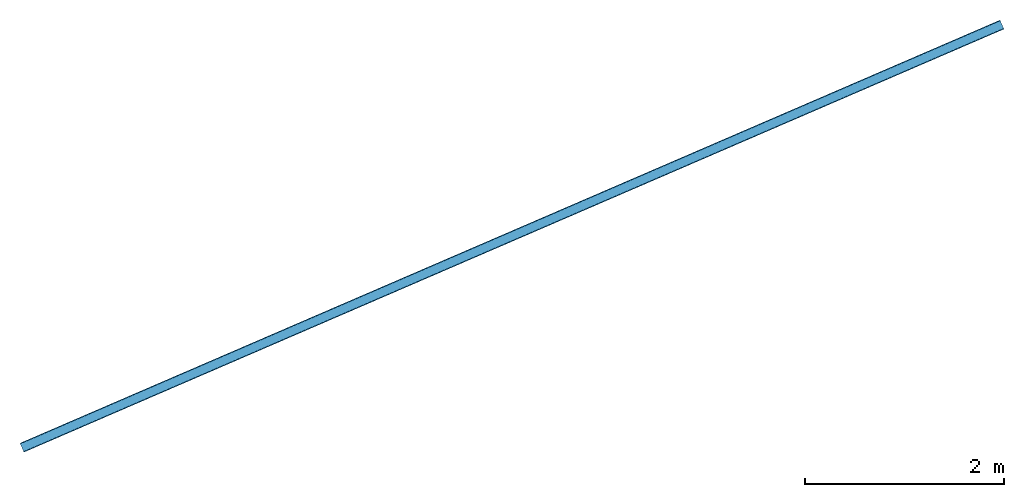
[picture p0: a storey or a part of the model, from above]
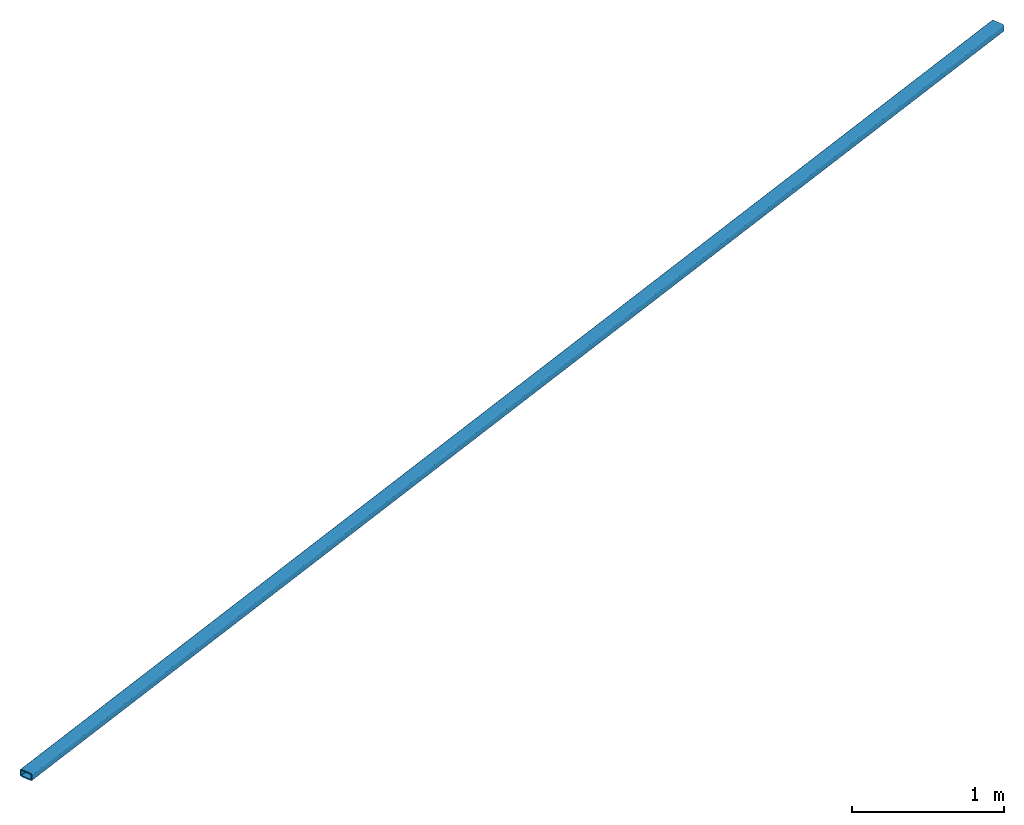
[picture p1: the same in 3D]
Properties of the parts of a building model (IFC4)

# File
Description: ViewDefinition [ReferenceView_V1.2], RevitIdentifiers [ContentGUID: 571f5c7f-810b-4b2c-baeb-ece62dd2b8b9, VersionGUID: cf4ed1ed-50e6-4d82-a1ad-c18ab90050e2, NumberOfSaves: 3], CoordinateReference [CoordinateBase: Shared Coordinates, ProjectSite: Interno]
File name: C:\Users\Joaquin\Dropbox\BuildingProjects\2024 - Construcción Cesfam Coyhaique Con Sar Adosado\2_Modelos\all_models_2025-1-24_23.4.48\CCY_COOR-CCY_EST_CubAmb_Enriched.ifc
Time: 2025-10-28T00:34:42-03:00
Written by: IfcOpenShell 0.8.3-post1
Made in: Bonsai 0.8.3-post1

# IfcProject, 2016_3
LongName: CESFAM Coyhaique; Phase: 3

# IfcSite, Default
RefLatitude: 42, 21, 31, 181945; RefLongitude: -71, -3, -24, -263305; RefElevation: 0 m
Pset_SiteCommon - Reference: Project Information
Other - Category: Project Information; Client Name: Servicio de Salud Aysén; Project Address: Calle 2, s/n. Lote 1C.; Project Issue Date: Marzo 2017; Project Name: CESFAM Coyhaique; Project Number: 2016_3; Project Status: 3
Identity Data - Author: Astudillo y Aparicio Asociados Ltda.; Organization Description: Arquitectura e ingeniería integrada; Organization Name: Astudillo y Aparicio Asociados Ltda.

# IfcBuilding
Pset_BuildingCommon - Reference: Project Information; NumberOfStoreys: 3
Pset_BuildingElementProxyCommon - Reference: Project Information; IsExternal: no
Pset_BuildingSystemCommon - Reference: Project Information
Other - Category: Project Information; Client Name: Servicio de Salud Aysén; Project Address: Calle 2, s/n. Lote 1C.; Project Issue Date: Marzo 2017; Project Name: CESFAM Coyhaique; Project Number: 2016_3; Project Status: 3
Identity Data - Author: Astudillo y Aparicio Asociados Ltda.; Organization Description: Arquitectura e ingeniería integrada; Organization Name: Astudillo y Aparicio Asociados Ltda.

# IfcBuildingStorey: Level:8mm Head (3)
Other - Category: Levels; Family: Level; Family and Type: Level: 8mm Head; Type: 8mm Head; Type Id: 27
Dimensions - Computation Height: 0 m
Identity Data - Structural: no; Building Story: yes
Other(Type) - Category: Levels; Family Name: Level
Constraints(Type) - Elevation Base: Project Base Point
Graphics(Type) - Color: 0; Line Pattern: Center; Line Weight: 1; Symbol: M_Level Head - Circle; Symbol at End 1 Default: no; Symbol at End 2 Default: yes
Identity Data(Type) - Type Name: 8mm Head
Name | LongName = Name | Elevation (m) = Constraints, Elevation (m)
Level 1 | Level 1 | 0
Level 2 | Level 2 | 4.25
Level 3 | Level 3 | 6.875

# IfcBeam: M_HSS Cuadrado:10x6 (3)
Type - PredefinedType: BEAM; Material: Acero, 45-345
Type - Other - Category: Structural Framing; Family Name: M_HSS Cuadrado
Type - Dimensions - Wall Design Thickness: 0.00886 m
Type - Identity Data - Code Name: AISC 14.1; OmniClass Number: 23.25.30.11.14.14; OmniClass Title: Beams; Section Name Key: HSS 6X6X3/8; Type Name: 10x6
Type - Structural - Section Shape: 14
Type - Structural Analysis - Elastic Modulus strong axis: 0.000216 m3; Elastic Modulus weak axis: 0.000216 m3; Moment of Inertia strong axis: 0.0000164 m4; Moment of Inertia weak axis: 0.0000164 m4; Nominal Weight: 400.11 kg/s2; Plastic Modulus strong axis: 0.000259 m3; Plastic Modulus weak axis: 0.000259 m3; Section Area: 0.00489 m2; Torsional Modulus: 5.93212 m3; Torsional Moment of Inertia: 0.0000269 m4
Type - Structural Section Geometry - Centroid Horizontal: 0.05 m; Centroid Vertical: 0.03 m; Height: 0.06 m; Inner Fillet: 0.00347 m; Outer Fillet: 0.013 m; Wall Nominal Thickness: 0.00953 m; Width: 0.1 m
Type - Pset_BeamCommon - LoadBearing: yes
Classification: B103 (FEMAP58); Material: Acero, 45-345; Acero, 45-345
Pset_BeamCommon - Slope: 0 deg; Roll: 0 deg; IsExternal: no; Reference: M_HSS Cuadrado:10x6; Span: 10.715 m
Pset_EnvironmentalImpactIndicators - Reference: M_HSS Cuadrado:10x6; sets with these values: 2
Qto_BeamBaseQuantities - Length: 10.715 m; CrossSectionArea: 0.00585482 m2; OuterSurfaceArea: 3.18966 m2; GrossSurfaceArea: 3.20137 m2; NetSurfaceArea: 5.74281 m2; GrossVolume: 0.0627344 m3; NetVolume: 0.0273398 m3
Other - Family: M_HSS Cuadrado; Family and Type: M_HSS Cuadrado: 10x6; Type: 10x6; Type Id: 204418
Constraints - Cross-Section Rotation: 0 deg
Dimensions - Length: 10.715 m; Volume: 0.0273398 m3
Materials and Finishes - Structural Material: Acero, 45-345
Phasing - Phase Created: New Construction
Structural - Stick Symbol Location: Center of Geometry; Structural Usage: Other; Cut Length: 10.715 m; Weight: 411.261 kg
Geometric Position - End Extension: 0 m; Join Status: Both joins enabled; Start Extension: 0 m; y Justification: Origin; y Offset Value: 0 m; yz Justification: Uniform; z Justification: Center; z Offset Value: 0 m
AboveGround - AboveGround: yes
Name (M_HSS Cuadrado:10x6:...) | In | Reference Level | Reference Level Elevation (m) | End Level Offset (m) = Start Level Offset (m) | Elevation at Bottom (m) | Elevation at Top (m)
205633 | Level 1 | Level 1 | 0 | 0.2 | 0.17 | 0.23
206063 | Level 2 | Level 2 | 4.25 | 0 | 4.22 | 4.28
206123 | Level 3 | Level 3 | 6.875 | -0.03 | 6.815 | 6.875

# IfcBeam: M_HSS-Tubo estructural redondo:HSS190.5X12.7 (9)
In: Level 1
Type - PredefinedType: BEAM; Material: Acero, 45-345
Type - Other - Category: Structural Framing; Family Name: M_HSS-Tubo estructural redondo
Type - Dimensions - OD: 0.15 m; t: 0.0118 m
Type - Identity Data - OmniClass Number: 23.25.30.11.14.14; OmniClass Title: Beams; Type Name: HSS190.5X12.7
Type - Structural - A: 0.00663 m2; Section Shape: 0; W: 0.546
Type - Pset_BeamCommon - LoadBearing: yes
Classification: B103 (FEMAP58); Material: Acero, 45-345; Acero, 45-345
Pset_BeamCommon - Reference: M_HSS-Tubo estructural redondo:HSS190.5X12.7; Slope: 0 deg; Roll: 0 deg; IsExternal: no
Pset_EnvironmentalImpactIndicators - Reference: M_HSS-Tubo estructural redondo:HSS190.5X12.7; sets with these values: 2
Qto_BeamBaseQuantities - CrossSectionArea: 0.0176691 m2
Other - Family: M_HSS-Tubo estructural redondo; Family and Type: M_HSS-Tubo estructural redondo: HSS190.5X12.7; Type: HSS190.5X12.7; Type Id: 199820
Constraints - Cross-Section Rotation: 0 deg; End Level Offset: 0 m; Orientation: Normal; Reference Level: Level 1; Reference Level Elevation: 0 m; Start Level Offset: 0 m; Work Plane: Level : Level 1
Dimensions - Elevation at Bottom: -0.075 m; Elevation at Top: 0.075 m
Materials and Finishes - Structural Material: Acero, 45-345
Phasing - Phase Created: New Construction
Structural - Stick Symbol Location: Center of Geometry; Structural Usage: Other; Weight: 0 kg
Geometric Position - End Extension: 0 m; Join Status: Both joins enabled; y Justification: Origin; y Offset Value: 0 m; yz Justification: Uniform; z Justification: Center; z Offset Value: 0 m
AboveGround - AboveGround: yes
Name (M_HSS-Tubo estructural redondo:HSS190.5X12.7:...) | Span (m) = Qto_BeamBaseQuantities, Length (m) = Dimensions, Length (m) | OuterSurfaceArea (m2) | GrossSurfaceArea (m2) | NetSurfaceArea (m2) | GrossVolume (m3) | NetVolume (m3) = Volume (m3) | Cut Length (m) | End Join Cutback (m) | Start Extension (m) | Start Join Cutback (m)
199774 | 4.12 | 1.82377 | 1.85911 | 3.37084 | 0.0683823 | 0.0198234 | 3.87017 | 0.174835 | 0
199776 | 10.8 | 5.08941 | 5.12475 | 9.38832 | 0.190827 | 0.0553189 | 10.8001 | -0.159597 | 0 | -0.0750596
199778 | 4.12 | 1.77745 | 1.81279 | 3.28549 | 0.0666456 | 0.0193199 | 3.77187 |  | -0.391851 | 0.140143
199781 | 5.65043 | 2.47751 | 2.51285 | 4.57548 | 0.0928944 | 0.0269387 | 5.25745 | 0.0127 | 0 | 0.0127
199783 | 5.64068 | 2.47751 | 2.51285 | 4.57547 | 0.0928944 | 0.0269292 | 5.25745 | 0.0127 | 0 | 0.0127
199785 | 5.64068 | 2.47751 | 2.51285 | 4.57547 | 0.0928944 | 0.0269292 | 5.25745 | 0.0127 | 0 | 0.0127
199787 | 4.12 | 1.76111 | 1.79644 | 3.25537 | 0.0660326 | 0.0191422 | 3.73718 | 0.174835 | 0
199789 | 4.12 | 1.82377 | 1.85911 | 3.37084 | 0.0683823 | 0.0198234 | 3.87017 | 0.174835 | 0
199791 | 10.8062 | 5.10892 | 5.14426 | 9.42429 | 0.191559 | 0.0555508 | 10.8415 |  | 0

# IfcCurtainWall: Curtain Wall:MC1 (3)
In: Level 1
Type - Other - Category: Walls; Family Name: Curtain Wall
Type - Construction - Automatically Embed: yes; Curtain Panel: System Panel : Glazed; Function: Exterior; Join Condition: Vertical Grid Continuous
Type - Identity Data - Type Name: MC1
Type - Horizontal Grid - Adjust for Mullion Size: no; Layout: Fixed Distance; Spacing: 5 m
Type - Vertical Grid - Adjust for Mullion Size: no; Layout: Maximum Spacing; Spacing: 1 m
Type - Horizontal Mullions - Border 1 Type: Rectangular Mullion : 50mm x 150mm; Border 2 Type: Rectangular Mullion : 50mm x 150mm; Interior Type: Rectangular Mullion : 50mm x 150mm
Type - Vertical Mullions - Border 1 Type: Rectangular Mullion : 50mm x 150mm; Border 2 Type: Rectangular Mullion : 50mm x 150mm; Interior Type: Rectangular Mullion : 50mm x 150mm
Classification: B2022 (FEMAP58)
Pset_CurtainWallCommon - Reference: Curtain Wall:MC1; IsExternal: yes
Pset_EnvironmentalImpactIndicators - Reference: Curtain Wall:MC1
Qto_CurtainWallQuantities - Height: 4.4 m; Width: 0.025 m
Other - Family: Curtain Wall; Family and Type: Curtain Wall: MC1; Type: MC1; Type Id: 206753
Constraints - Base is Attached: no; Related to Mass: no; Room Bounding: yes; Top is Attached: no; Top Offset: 0 m; Base Constraint: Level 1; Base Offset: -0.15 m; Top Constraint: Up to level: Level 2; Unconnected Height: 4.4 m
Phasing - Phase Created: New Construction
Structural - Structural: no; Structural Usage: Non-bearing
Horizontal Grid - Angle: 0 deg; Justification: Beginning; Number: 1; Offset: 0 m
Vertical Grid - Angle: 0 deg; Justification: Beginning; Offset: 0 m
Cross-Section Definition - Cross-Section: Vertical
AboveGround - AboveGround: yes
Name (Curtain Wall:MC1:...) | Pset_WallArea, Area (m2) = GrossSideArea (m2) = NetSideArea (m2) = Dimensions, Area (m2) | Qto_CurtainWallQuantities, Length (m) = Dimensions, Length (m) | Number
206290 | 19.36 | 4.4 | 4
207053 | 19.36 | 4.4 | 4
207141 | 49.5 | 11.25 | 11

# IfcGrid (3)
AboveGround - AboveGround: yes
Name | In
Default Grid | Level 1
Default Grid | Level 2
Default Grid | Level 3

# IfcMember: M_HSS Cuadrado:10x6 (4)
In: Level 1
Type - PredefinedType: BRACE; Material: Acero, 45-345
Type - Other - Category: Structural Framing; Family Name: M_HSS Cuadrado
Type - Dimensions - Wall Design Thickness: 0.00886 m
Type - Identity Data - Code Name: AISC 14.1; OmniClass Number: 23.25.30.11.14.14; OmniClass Title: Beams; Section Name Key: HSS 6X6X3/8; Type Name: 10x6
Type - Structural - Section Shape: 14
Type - Structural Analysis - Elastic Modulus strong axis: 0.000216 m3; Elastic Modulus weak axis: 0.000216 m3; Moment of Inertia strong axis: 0.0000164 m4; Moment of Inertia weak axis: 0.0000164 m4; Nominal Weight: 400.11 kg/s2; Plastic Modulus strong axis: 0.000259 m3; Plastic Modulus weak axis: 0.000259 m3; Section Area: 0.00489 m2; Torsional Modulus: 5.93212 m3; Torsional Moment of Inertia: 0.0000269 m4
Type - Structural Section Geometry - Centroid Horizontal: 0.05 m; Centroid Vertical: 0.03 m; Height: 0.06 m; Inner Fillet: 0.00347 m; Outer Fillet: 0.013 m; Wall Nominal Thickness: 0.00953 m; Width: 0.1 m
Type - Pset_MemberCommon - LoadBearing: yes
Classification: B1033 (FEMAP58); Material: Acero, 45-345; Acero, 45-345
Pset_EnvironmentalImpactIndicators - Reference: M_HSS Cuadrado:10x6
Pset_MemberCommon - Slope: 0 deg; Roll: 0 deg; IsExternal: no; Reference: M_HSS Cuadrado:10x6
Qto_MemberBaseQuantities - CrossSectionArea: 0.00585482 m2
Other - Family: M_HSS Cuadrado; Family and Type: M_HSS Cuadrado: 10x6; Type: 10x6; Type Id: 204418
Constraints - Cross-Section Rotation: 0 deg; Reference Level: Level 1; Reference Level Elevation: 0 m
Materials and Finishes - Structural Material: Acero, 45-345
Phasing - Phase Created: New Construction
Structural - Structural Usage: Other; Start Attachment Type: Distance
Geometric Position - End Extension: 0 m; Join Status: Both joins enabled; Start Extension: 0 m; y Justification: Origin; y Offset Value: 0 m; yz Justification: Uniform; z Offset Value: 0 m; z Justification: Origin; Start Join Cutback: 0.0127 m
AboveGround - AboveGround: yes
Name (M_HSS Cuadrado:10x6:...) | Span (m) = Qto_MemberBaseQuantities, Length (m) = Dimensions, Length (m) | OuterSurfaceArea (m2) | GrossSurfaceArea (m2) | NetSurfaceArea (m2) | GrossVolume (m3) | NetVolume (m3) = Volume (m3) | Start Attachment Distance (m) | Start of Attachment to Reference Element | Cut Length (m) | Weight (kg)
204370 | 6.645 | 1.95267 | 1.96438 | 3.51766 | 0.0384053 | 0.0167371 | 0 | Start | 6.5596 | 251.77 | Structural - End Attachment Distance: 0 m; End Attachment Type: Distance; End of Attachment to Reference Element: Start; Geometric Position - End Join Cutback: 0.0127 m
204372 | 6.645 | 1.95267 | 1.96438 | 3.51766 | 0.0384053 | 0.0167371 | 0.0000298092 | End | 6.5596 | 251.77 | Structural - End Attachment Distance: 0.0000298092 m; End Attachment Type: Distance; End of Attachment to Reference Element: End; Geometric Position - End Join Cutback: 0.0127 m
204374 | 6.245 | 1.84631 | 1.85802 | 3.32634 | 0.0363134 | 0.0158255 | 3.57009 | End | 6.2023 | 238.056 | Structural - End Attachment Elevation: 0.6 m; End Attachment Level Reference: Level 1
204376 | 6.265 | 1.85226 | 1.86397 | 3.33705 | 0.0364305 | 0.0158765 | 3.54497 | Start | 6.2223 | 238.823 | Structural - End Attachment Elevation: 0.58 m; End Attachment Level Reference: Level 1

# IfcMember: M_HSS-Tubo estructural redondo:HSS190.5X12.7 (4)
In: Level 1
Type - PredefinedType: BRACE; Material: Acero, 45-345
Type - Other - Category: Structural Framing; Family Name: M_HSS-Tubo estructural redondo
Type - Dimensions - OD: 0.15 m; t: 0.0118 m
Type - Identity Data - OmniClass Number: 23.25.30.11.14.14; OmniClass Title: Beams; Type Name: HSS190.5X12.7
Type - Structural - A: 0.00663 m2; Section Shape: 0; W: 0.546
Type - Pset_MemberCommon - LoadBearing: yes
Classification: B1033 (FEMAP58); Material: Acero, 45-345; Acero, 45-345
Pset_EnvironmentalImpactIndicators - Reference: M_HSS-Tubo estructural redondo:HSS190.5X12.7
Pset_MemberCommon - Reference: M_HSS-Tubo estructural redondo:HSS190.5X12.7; Roll: 0 deg; IsExternal: no
Qto_MemberBaseQuantities - CrossSectionArea: 0.0176691 m2
Other - Family: M_HSS-Tubo estructural redondo; Family and Type: M_HSS-Tubo estructural redondo: HSS190.5X12.7; Type: HSS190.5X12.7; Type Id: 199820
Constraints - Cross-Section Rotation: 0 deg; Reference Level: Level 1; Reference Level Elevation: 0 m
Materials and Finishes - Structural Material: Acero, 45-345
Phasing - Phase Created: New Construction
Structural - Structural Usage: Other; Weight: 0 kg; End Attachment Level Reference: Level 2; Start Attachment Type: Distance
Geometric Position - End Extension: 0 m; Join Status: Both joins enabled; Start Extension: 0 m; y Justification: Origin; y Offset Value: 0 m; yz Justification: Uniform; z Offset Value: 0 m; z Justification: Origin
AboveGround - AboveGround: yes
Name (M_HSS-Tubo estructural redondo:HSS190.5X12.7:...) | Span (m) = Qto_MemberBaseQuantities, Length (m) = Dimensions, Length (m) | Slope (deg) | OuterSurfaceArea (m2) | GrossSurfaceArea (m2) | NetSurfaceArea (m2) | GrossVolume (m3) | NetVolume (m3) = Volume (m3) | Cut Length (m) | End Attachment Elevation (m) | Start Attachment Distance (m) | Start of Attachment to Reference Element | Start Join Cutback (m)
203480 | 5.86537 | 44.332 | 2.58501 | 2.62035 | 4.77356 | 0.096925 | 0.0280976 | 5.48557 | -0.151195 | 3.6 | End | 0.273741
203482 | 5.80537 | 44.3314 | 2.50803 | 2.54337 | 4.63171 | 0.0940386 | 0.0272609 | 5.32221 | -0.193163 | 0 | End | 0.299063
203484 | 5.86537 | 44.332 | 2.55353 | 2.58887 | 4.71555 | 0.0957446 | 0.0277554 | 5.41876 | -0.151195 | 3.6 | Start | 0.340546
203486 | 5.88 | 44.3833 | 2.56234 | 2.59767 | 4.73177 | 0.0960747 | 0.0278511 | 5.43745 | -0.137206 | 0.00750763 | End | 0.258696

# IfcMember: Rectangular Mullion:50mm x 150mm (69)
In: Level 1
Type - PredefinedType: MULLION; Material: Aluminum
Type - Other - Category: Curtain Wall Mullions; Family Name: Rectangular Mullion
Type - Constraints - Angle: 0 deg; Offset: 0 m
Type - Construction - Corner Mullion: no; Position: Perpendicular to Face; Thickness: 0.15 m
Type - Dimensions - Width on side 1: 0.025 m; Width on side 2: 0.025 m
Type - Identity Data - Type Name: 50mm x 150mm
Type - Materials and Finishes - Material: Aluminum
Pset_EnvironmentalImpactIndicators - Reference: Rectangular Mullion:50mm x 150mm
Pset_MemberCommon - IsExternal: yes; Reference: Rectangular Mullion:50mm x 150mm
Other - Family: Rectangular Mullion; Family and Type: Rectangular Mullion: 50mm x 150mm; Type: 50mm x 150mm; Type Id: 29421
Constraints - Level: Level 1
Phasing - Phase Created: New Construction
Name (Rectangular Mullion:50mm x 150mm:...) | Span (m) = Qto_MemberBaseQuantities, Length (m) = Dimensions, Length (m) | CrossSectionArea (m2) = Area (m2) | NetSurfaceArea (m2) | NetVolume (m3) = Volume (m3) | Host Id
206313 | 0.805 | 0.1685 | 0.337 | 0.0060375 | 206290
206314 | 0.805 | 0.1685 | 0.337 | 0.0060375 | 206290
206315 | 0.83 | 0.1735 | 0.347 | 0.006225 | 206290
206316 | 0.805 | 0.1685 | 0.337 | 0.0060375 | 206290
206317 | 0.83 | 0.1735 | 0.347 | 0.006225 | 206290
206318 | 0.83 | 0.1735 | 0.347 | 0.006225 | 206290
206319 | 4.4 | 0.8875 | 1.775 | 0.033 | 206290
206323 | 4.4 | 0.8875 | 1.775 | 0.033 | 206290
206336 | 4.4 | 0.8875 | 1.775 | 0.033 | 206290
206337 | 4.4 | 0.8875 | 1.775 | 0.033 | 206290
206837 | 0.83 | 0.1735 | 0.347 | 0.006225 | 206290
206838 | 0.83 | 0.1735 | 0.347 | 0.006225 | 206290
206839 | 0.83 | 0.1735 | 0.347 | 0.006225 | 206290
206840 | 0.805 | 0.1685 | 0.337 | 0.0060375 | 206290
206843 | 4.4 | 0.8875 | 1.775 | 0.033 | 206290
206844 | 4.4 | 0.8875 | 1.775 | 0.033 | 206290
207059 | 0.805 | 0.1685 | 0.337 | 0.0060375 | 207053
207060 | 0.805 | 0.1685 | 0.337 | 0.0060375 | 207053
207061 | 0.83 | 0.1735 | 0.347 | 0.006225 | 207053
207062 | 0.805 | 0.1685 | 0.337 | 0.0060375 | 207053
207063 | 0.83 | 0.1735 | 0.347 | 0.006225 | 207053
207064 | 0.83 | 0.1735 | 0.347 | 0.006225 | 207053
207065 | 4.4 | 0.8875 | 1.775 | 0.033 | 207053
207066 | 4.4 | 0.8875 | 1.775 | 0.033 | 207053
207067 | 4.4 | 0.8875 | 1.775 | 0.033 | 207053
207068 | 4.4 | 0.8875 | 1.775 | 0.033 | 207053
207073 | 0.83 | 0.1735 | 0.347 | 0.006225 | 207053
207074 | 0.83 | 0.1735 | 0.347 | 0.006225 | 207053
207075 | 0.83 | 0.1735 | 0.347 | 0.006225 | 207053
207076 | 0.805 | 0.1685 | 0.337 | 0.0060375 | 207053
207077 | 4.4 | 0.8875 | 1.775 | 0.033 | 207053
207078 | 4.4 | 0.8875 | 1.775 | 0.033 | 207053
207147 | 0.8625 | 0.18 | 0.36 | 0.00646875 | 207141
207149 | 0.8875 | 0.185 | 0.37 | 0.00665625 | 207141
207150 | 0.8625 | 0.18 | 0.36 | 0.00646875 | 207141
207152 | 0.8875 | 0.185 | 0.37 | 0.00665625 | 207141
207153 | 4.4 | 0.8875 | 1.775 | 0.033 | 207141
207154 | 4.4 | 0.8875 | 1.775 | 0.033 | 207141
207156 | 4.4 | 0.8875 | 1.775 | 0.033 | 207141
207161 | 0.8875 | 0.185 | 0.37 | 0.00665625 | 207141
207162 | 0.8875 | 0.185 | 0.37 | 0.00665625 | 207141
207163 | 0.8875 | 0.185 | 0.37 | 0.00665625 | 207141
207164 | 0.8625 | 0.18 | 0.36 | 0.00646875 | 207141
207165 | 4.4 | 0.8875 | 1.775 | 0.033 | 207141
207166 | 4.4 | 0.8875 | 1.775 | 0.033 | 207141
207270 | 0.8625 | 0.18 | 0.36 | 0.00646875 | 207141
207271 | 0.8875 | 0.185 | 0.37 | 0.00665625 | 207141
207272 | 0.8875 | 0.185 | 0.37 | 0.00665625 | 207141
207273 | 0.8875 | 0.185 | 0.37 | 0.00665625 | 207141
207274 | 0.8875 | 0.185 | 0.37 | 0.00665625 | 207141
207275 | 0.8875 | 0.185 | 0.37 | 0.00665625 | 207141
207276 | 0.8875 | 0.185 | 0.37 | 0.00665625 | 207141
207277 | 0.8875 | 0.185 | 0.37 | 0.00665625 | 207141
207278 | 0.8875 | 0.185 | 0.37 | 0.00665625 | 207141
207279 | 0.8875 | 0.185 | 0.37 | 0.00665625 | 207141
207280 | 0.8875 | 0.185 | 0.37 | 0.00665625 | 207141
207281 | 0.8875 | 0.185 | 0.37 | 0.00665625 | 207141
207282 | 0.8875 | 0.185 | 0.37 | 0.00665625 | 207141
207283 | 0.8875 | 0.185 | 0.37 | 0.00665625 | 207141
207284 | 0.8875 | 0.185 | 0.37 | 0.00665625 | 207141
207285 | 0.8875 | 0.185 | 0.37 | 0.00665625 | 207141
207286 | 4.4 | 0.8875 | 1.775 | 0.033 | 207141
207287 | 4.4 | 0.8875 | 1.775 | 0.033 | 207141
207288 | 4.4 | 0.8875 | 1.775 | 0.033 | 207141
207289 | 4.4 | 0.8875 | 1.775 | 0.033 | 207141
207290 | 4.4 | 0.8875 | 1.775 | 0.033 | 207141
207291 | 4.4 | 0.8875 | 1.775 | 0.033 | 207141
207292 | 4.4 | 0.8875 | 1.775 | 0.033 | 207141
207293 | 4.4 | 0.8875 | 1.775 | 0.033 | 207141

# IfcMember: Union Metalica 2:Union Metalica 2 (4)
In: Level 1
Type - PredefinedType: PLATE; Material: <Unnamed>
Type - Other - Category: Generic Models; Family Name: Union Metalica 2
Type - Constraints - Default Elevation: 0 m
Type - Identity Data - Type Name: Union Metalica 2
Pset_BuildingElementProxyCommon - IsExternal: no; Reference: Union Metalica 2:Union Metalica 2
Pset_EnvironmentalImpactIndicators - Reference: Union Metalica 2:Union Metalica 2
Qto_BuildingElementProxyQuantities - NetSurfaceArea: 0.622312 m2; NetVolume: 0.0053543 m3
Other - Family: Union Metalica 2; Family and Type: Union Metalica 2: Union Metalica 2; Type: Union Metalica 2; Type Id: 200722
Constraints - Elevation from Level: 0 m; Host: Level : Level 1; Level: Level 1; Moves With Nearby Elements: no; Offset from Host: 0 m
Dimensions - Area: 0.311156 m2; Volume: 0.0053543 m3
Phasing - Phase Created: New Construction
AboveGround - AboveGround: yes
Name (Union Metalica 2:Union Metalica 2:...)
200694
200695
200696
200697

# IfcMember: Union Metalica 3:Union Metalica 3 (4)
In: Level 2
Type - PredefinedType: PLATE; Material: <Unnamed>
Type - Other - Category: Generic Models; Family Name: Union Metalica 3
Type - Constraints - Default Elevation: 0 m
Type - Dimensions - Angulo: 90 deg
Type - Identity Data - Type Name: Union Metalica 3
Pset_BuildingElementProxyCommon - IsExternal: no; Reference: Union Metalica 3:Union Metalica 3
Pset_EnvironmentalImpactIndicators - Reference: Union Metalica 3:Union Metalica 3
Qto_BuildingElementProxyQuantities - NetSurfaceArea: 0.622249 m2; NetVolume: 0.00535387 m3
Other - Family: Union Metalica 3; Family and Type: Union Metalica 3: Union Metalica 3; Type: Union Metalica 3; Type Id: 203512
Constraints - Elevation from Level: 0 m; Moves With Nearby Elements: no; Offset from Host: 0 m; Level: Level 2; Host: Level : Level 2
Dimensions - Area: 0.311124 m2; Volume: 0.00535387 m3
Phasing - Phase Created: New Construction
AboveGround - AboveGround: yes
Name (Union Metalica 3:Union Metalica 3:...)
203488
203489
203490
203491

# IfcMember: Union Metalica 4:Union Metalica 4, Union Metalica 4:Union Metalica 4:201819
In: Level 2
Type - PredefinedType: PLATE; Material: <Unnamed>
Type - Other - Category: Structural Connections; Family Name: Union Metalica 4
Type - Dimensions - Ancho placa: 0.04 m; Ancho tubo: 0.13 m
Type - Identity Data - Type Name: Union Metalica 4
Pset_BuildingElementProxyCommon - IsExternal: no; Reference: Union Metalica 4:Union Metalica 4
Pset_EnvironmentalImpactIndicators - Reference: Union Metalica 4:Union Metalica 4
Qto_BuildingElementProxyQuantities - NetSurfaceArea: 1.13453 m2; NetVolume: 0.0173972 m3
Other - Family: Union Metalica 4; Family and Type: Union Metalica 4: Union Metalica 4; Type: Union Metalica 4; Type Id: 201860
Constraints - Moves With Nearby Elements: no; Level: Level 2; Host: Level : Level 2; Offset from Host: -4.25 m
Dimensions - Area: 0.567265 m2; Volume: 0.0173972 m3
Phasing - Phase Created: New Construction
Structural - Rebar Cover: Rebar Cover 1 <25 mm>
AboveGround - AboveGround: yes

# IfcMember: Union Metalica:Union Metalica (3)
In: Level 2
Type - PredefinedType: PLATE; Material: <Unnamed>
Type - Other - Category: Structural Connections; Family Name: Union Metalica
Type - Dimensions - Ancho placa: 0.04 m; Ancho tubo: 0.0731969 m
Type - Identity Data - Type Name: Union Metalica
Pset_BuildingElementProxyCommon - IsExternal: no; Reference: Union Metalica:Union Metalica
Pset_EnvironmentalImpactIndicators - Reference: Union Metalica:Union Metalica
Qto_BuildingElementProxyQuantities - NetSurfaceArea: 0.909347 m2; NetVolume: 0.0154191 m3
Other - Family: Union Metalica; Family and Type: Union Metalica: Union Metalica; Type: Union Metalica; Type Id: 201863
Constraints - Moves With Nearby Elements: no; Host: Level : Level 2; Level: Level 2; Offset from Host: -4.25 m
Dimensions - Area: 0.454673 m2; Volume: 0.0154191 m3
Phasing - Phase Created: New Construction
Structural - Rebar Cover: Rebar Cover 1 <25 mm>
AboveGround - AboveGround: yes
Name (Union Metalica:Union Metalica:...)
201816
201817
201818

# IfcPlate: System Panel:Glazed (22)
In: Level 1
Type - PredefinedType: CURTAIN_PANEL; Material: Glass
Type - Other - Category: Curtain Panels; Family Name: System Panel
Type - Constraints - Offset: 0.037 m
Type - Dimensions - Thickness: 0.025 m
Type - Identity Data - Type Name: Glazed
Type - Materials and Finishes - Material: Glass
Type - Analytical Properties - Analytic Construction: <None>; Define Thermal Properties by: Schematic Type
Pset_EnvironmentalImpactIndicators - Reference: System Panel:Glazed
Pset_PlateCommon - IsExternal: yes; Reference: System Panel:Glazed
Other - Family: System Panel; Family and Type: System Panel: Glazed; Type: Glazed; Type Id: 22643
Constraints - Level: Level 1
Dimensions - Height: 4.3 m
Phasing - Phase Created: New Construction
Name (System Panel:Glazed:...) | Qto_PlateBaseQuantities, Width (m) = Dimensions, Width (m) | GrossArea (m2) = NetArea (m2) = Area (m2) | NetVolume (m3) = Volume (m3) | Host Id
206291 | 0.805 | 3.4615 | 0.0865375 | 206290
206296 | 0.83 | 3.569 | 0.089225 | 206290
206298 | 0.83 | 3.569 | 0.089225 | 206290
206821 | 0.83 | 3.569 | 0.089225 | 206290
206824 | 0.805 | 3.4615 | 0.0865375 | 206290
207054 | 0.805 | 3.4615 | 0.0865375 | 207053
207056 | 0.83 | 3.569 | 0.089225 | 207053
207058 | 0.83 | 3.569 | 0.089225 | 207053
207070 | 0.83 | 3.569 | 0.089225 | 207053
207072 | 0.805 | 3.4615 | 0.0865375 | 207053
207142 | 0.8625 | 3.70875 | 0.0927188 | 207141
207263 | 0.8875 | 3.81625 | 0.0954062 | 207141
207261 | 0.8875 | 3.81625 | 0.0954062 | 207141
207259 | 0.8875 | 3.81625 | 0.0954062 | 207141
207257 | 0.8875 | 3.81625 | 0.0954062 | 207141
207255 | 0.8875 | 3.81625 | 0.0954062 | 207141
207253 | 0.8875 | 3.81625 | 0.0954062 | 207141
207251 | 0.8875 | 3.81625 | 0.0954062 | 207141
207249 | 0.8875 | 3.81625 | 0.0954062 | 207141
207146 | 0.8875 | 3.81625 | 0.0954062 | 207141
207158 | 0.8875 | 3.81625 | 0.0954062 | 207141
207160 | 0.8625 | 3.70875 | 0.0927188 | 207141

# IfcWall: Basic Wall:Interior - bloques 140 mm (3)
In: Level 2
Type - PredefinedType: STANDARD; Material: Tablero de muro de yeso (2), Bloques de hormigón
Type - Other - Category: Walls; Family Name: Basic Wall
Type - Construction - Function: Interior; Width: 0.164 m; Wrapping at Inserts: Do not wrap
Type - Graphics - Coarse Scale Fill Color: 0
Type - Identity Data - Type Name: Interior - bloques 140 mm
Type - Materials and Finishes - Structural Material: Bloques de hormigón
Type - Analytical Properties - Absorptance: 0.7; Heat Transfer Coefficient (U): 6.91489 kg/K/s3; Roughness: 3; Thermal Mass: 233856; Thermal Resistance (R): 0.144615 s3*K/kg
Type - Pset_WallCommon - ThermalTransmittance: 6.91489 kg/K/s3
Classification: B1044 (FEMAP58)
Qto_WallBaseQuantities - Tablero de muro de yeso, Width: 0.012 m; Bloques de hormigón, Width: 0.14 m; Width: 0.164 m; Height: 2.625 m; Tablero de muro de yeso: 2 with these values
Pset_EnvironmentalImpactIndicators - Reference: Basic Wall:Interior - bloques 140 mm; sets with these values: 2
Pset_WallCommon - IsExternal: no; LoadBearing: yes; Reference: Basic Wall:Interior - bloques 140 mm; ExtendToStructure: no
Other - Family: Basic Wall; Family and Type: Basic Wall: Interior - bloques 140 mm; Type: Interior - bloques 140 mm; Type Id: 205489
Constraints - Base Constraint: Level 2; Base Extension Distance: 0 m; Base is Attached: no; Base Offset: 0 m; Location Line: Wall Centerline; Related to Mass: no; Room Bounding: yes; Top Constraint: Up to level: Level 3; Top Extension Distance: 0 m; Top is Attached: no; Top Offset: 0 m; Unconnected Height: 2.625 m
Phasing - Phase Created: New Construction
Structural - Rebar Cover - Exterior Face: Exterior - 10M a 16M <40 mm>; Rebar Cover - Interior Face: Interior (losas, muros, viguetas) - 10M a 36M <20 mm>; Rebar Cover - Other Faces: Interior (losas, muros, viguetas) - 10M a 36M <20 mm>; Structural: yes; Structural Usage: Bearing
Cross-Section Definition - Cross-Section: Vertical
AboveGround - AboveGround: yes
Name (Basic Wall:Interior - bloques 140 mm:...) | Qto_WallBaseQuantities, Length (m) = Pset_WallLength, Length (m) = Dimensions, Length (m) | GrossVolume (m3) = NetVolume (m3) = Volume (m3) | GrossSideArea (m2) = NetSideArea (m2) = Pset_WallArea, Area (m2) = Dimensions, Area (m2)
205483 | 4.6 | 2.0156 | 12.2902
205485 | 4.6 | 2.0156 | 12.2902
205487 | 11.114 | 4.71397 | 28.7437
